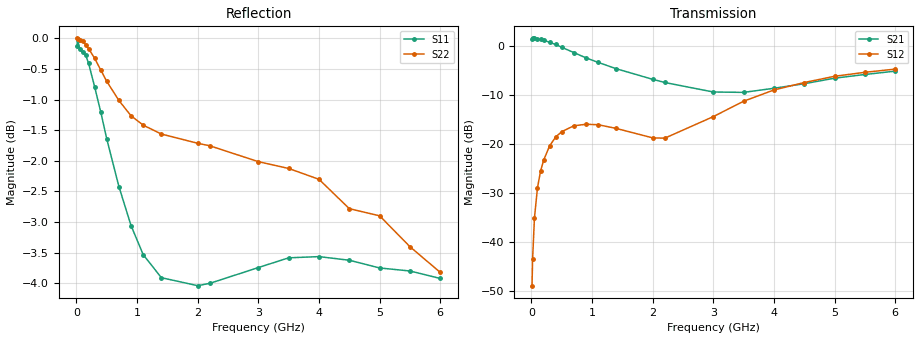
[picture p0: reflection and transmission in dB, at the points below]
! Infineon Technologies  Discrete & RF Semiconductors
! BFS17W
! Si NPN RF Bipolar Junction Transistor in SOT323
! VCE = 6 V  IC = 0.3 mA
! Common Emitter S-Parameters:  August  1999
# GHz  S  MA  R  50
!  f  S11  S21  S12  S22
! GHz  MAG  ANG  MAG  ANG  MAG  ANG  MAG  ANG
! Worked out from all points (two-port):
!   36 points, 10 MHz to 6 GHz, reference 50 ohm
!   highest |S21| = 1.57 dB at 20 MHz (marker M1); lowest = -9.4 dB at 3.5 GHz (marker M2)
!   |S21| within 3 dB of the highest: start of sweep to 718.9 MHz
!   lowest |S11| = -4.0 dB at 2 GHz (marker M3), VSWR 4.37, Z = 11.5 + j2.32 ohm
!   |S11| at or under -10 dB: nowhere
!   |S22| runs from -3.8 to 0.0 dB; largest |S21 - S12| = 1.2
!   S11 on the Smith chart (normalised r, x): 10 MHz: 32, -60; 300 MHz: 0.28, -2.23; 700 MHz: 0.24, -0.84; 1.4 GHz: 0.23, -0.22; 3 GHz: 0.24, +0.38; 6 GHz: 0.53, +1.11
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0.01  0.9862 -1.5  1.192 179.4  0.0036 86.1  0.9999 0.1
0.02  0.9976 -3.5  1.198 177.4  0.0068 85.6  0.999 -0.8
0.05  0.981 -8.3  1.195 173.0  0.0177 86.4  0.9971 -2.2
0.1  0.9742 -16.2  1.174 166.5  0.0358 80.3  0.9951 -4.4
0.15  0.9694 -25.2  1.169 159.3  0.0527 74.4  0.9883 -6.4
0.2  0.9538 -32.4  1.146 152.5  0.0681 70.4  0.9808 -8.4
0.3  0.9125 -47.8  1.094 139.8  0.0959 61.5  0.963 -12.2
0.4  0.8705 -62.0  1.038 127.8  0.1182 53.3  0.9421 -15.6
0.5  0.8272 -75.0  0.972 117.3  0.1339 46.4  0.922 -18.6
0.7  0.7565 -98.3  0.858 99.1  0.1538 35.7  0.8896 -24.0
0.9  0.703 -117.3  0.758 84.5  0.1594 27.9  0.8643 -29.0
1.1  0.6657 -133.8  0.682 72.3  0.1577 22.9  0.8493 -33.9
1.4  0.6374 -154.1  0.587 58.3  0.1445 19.3  0.8352 -41.4
2  0.6279 174.4  0.458 40.1  0.1158 32.2  0.8208 -57.7
2.2  0.6307 165.9  0.425 36.4  0.115 42.2  0.8169 -63.4
3  0.6497 136.4  0.34 34.7  0.1907 69.1  0.7929 -86.7
3.5  0.6617 121.3  0.337 39.2  0.2738 69.0  0.7828 -101.9
4  0.6632 108.8  0.371 42.2  0.3565 63.1  0.767 -118.3
4.5  0.6587 97.9  0.413 41.6  0.4246 55.6  0.7258 -133.6
5  0.6492 89.7  0.47 38.6  0.4917 48.2  0.7161 -147.4
5.5  0.6455 82.7  0.513 34.3  0.5398 40.8  0.6757 -161.6
6  0.6365 77.2  0.555 29.4  0.5819 34.1  0.6438 -173.8
